VERSION 5.8 ;
BUSBITCHARS "[]" ;
DIVIDERCHAR "/" ;

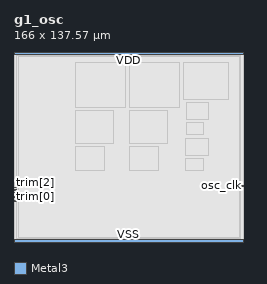
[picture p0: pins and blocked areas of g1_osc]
MACRO g1_osc
  CLASS BLOCK ;
  ORIGIN 0 0 ;
  FOREIGN g1_osc 0 0 ;
  SIZE 166 BY 137.57 ;
  SYMMETRY X Y ;
  PIN en
    DIRECTION INPUT ;
    USE SIGNAL ;
    PORT
      LAYER Metal3 ;
        RECT 0 29.5 1.5 29.8 ;
    END
  END en
  PIN trim[0]
    DIRECTION INPUT ;
    USE SIGNAL ;
    PORT
      LAYER Metal3 ;
        RECT 0 32.5 1.5 32.8 ;
    END
  END trim[0]
  PIN trim[1]
    DIRECTION INPUT ;
    USE SIGNAL ;
    PORT
      LAYER Metal3 ;
        RECT 0 35.5 1.5 35.8 ;
    END
  END trim[1]
  PIN trim[2]
    DIRECTION INPUT ;
    USE SIGNAL ;
    PORT
      LAYER Metal3 ;
        RECT 0 37.5 1.5 37.8 ;
    END
  END trim[2]
  PIN trim[3]
    DIRECTION INPUT ;
    USE SIGNAL ;
    PORT
      LAYER Metal3 ;
        RECT 0 39.5 1.5 39.8 ;
    END
  END trim[3]
  PIN osc_clk
    DIRECTION OUTPUT ;
    USE SIGNAL ;
    PORT
      LAYER Metal3 ;
        RECT 164.5 40.5 166 40.8 ;
    END
  END osc_clk
  PIN VDD
    DIRECTION INOUT ;
    USE POWER ;
    PORT
      LAYER Metal3 ;
        RECT 0 135.57 166 137.57 ;
    END
  END VDD
  PIN VSS
    DIRECTION INOUT ;
    USE GROUND ;
    PORT
      LAYER Metal3 ;
        RECT 0 0 166 2 ;
    END
  END VSS
  OBS
    LAYER Metal1 ;
      RECT 0 0 166 137.57 ;
    LAYER Metal2 ;
      RECT 0 0 166 137.57 ;
    LAYER Metal3 ;
      RECT 1.8 2.5 164.2 135.07 ;
    LAYER Metal4 ;
      RECT 3 3 163 134.57 ;
    LAYER Metal5 ;
      RECT 3 3 163 134.57 ;
    LAYER TopMetal1 ;
      RECT 44.38 51.625 65.355 69.005 ;
      RECT 44.38 71.185 71.885 94.865 ;
      RECT 44.38 97.145 80.575 129.645 ;
      RECT 83.88 51.625 104.855 69.005 ;
      RECT 83.88 71.185 111.385 94.865 ;
      RECT 83.88 97.145 120.075 129.645 ;
      RECT 122.88 103.47 155.1 129.67 ;
      RECT 123.88 51.95 137.36 60.51 ;
      RECT 123.88 62.915 140.945 75.255 ;
      RECT 124.88 77.66 137.36 86.22 ;
      RECT 124.88 88.625 140.945 100.965 ;
  END
END g1_osc

END LIBRARY
